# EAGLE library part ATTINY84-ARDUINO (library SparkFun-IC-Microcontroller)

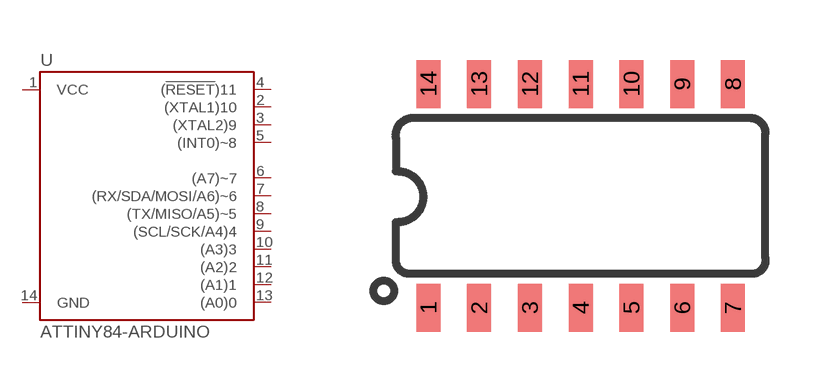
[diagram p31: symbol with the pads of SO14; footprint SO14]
Designator prefix U

## ATTINY84-ARDUINO (PROD_ID: IC-11285)  [SO14]
1  VCC
2  (XTAL1)10
3  (XTAL2)9
4  (!RESET!)11
5  (INT0)~8
6  (A7)~7
7  (RX/SDA/MOSI/A6)~6
8  (TX/MISO/A5)~5
9  (SCL/SCK/A4)4
10  (A3)3
11  (A2)2
12  (A1)1
13  (A0)0
14  GND

## Footprint SO14 (pad centres in mm)
SOIC, 0.15 inch width
smd 0.6 x 1.2: 1 -3.175,-2.8; 2 -1.905,-2.8; 3 -0.635,-2.8; 4 0.635,-2.8; 5 1.905,-2.8; 6 3.175,-2.8; 7 4.445,-2.8; 8 4.445,2.8; 9 3.175,2.8; 10 1.905,2.8; 11 0.635,2.8; 12 -0.635,2.8; 13 -1.905,2.8; 14 -3.175,2.8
